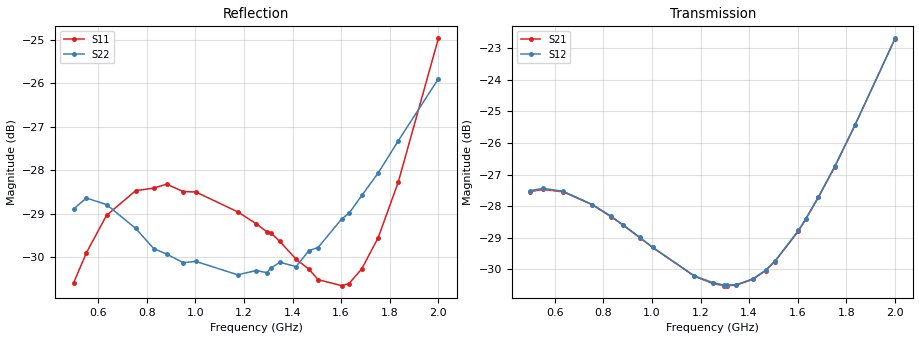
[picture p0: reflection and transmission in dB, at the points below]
!Agilent Technologies,E8363B,SG43030131,A.07.50.48
!Agilent E8363B: A.07.50.48
!Date: Wednesday, October 22, 2025 01:53:43
!Correction: S11(Full 2 Port(1,2))
!S21(Full 2 Port(1,2))
!S12(Full 2 Port(1,2))
!S22(Full 2 Port(1,2))
!S2P File: Measurements: S11, S21, S12, S22:
# Hz S  dB  R 50
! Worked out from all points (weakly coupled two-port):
!   201 points, 500 MHz to 2 GHz, reference 50 ohm
!   highest |S21| = -22.70 dB at 2 GHz (marker M1); lowest = -30.5 dB at 1.31 GHz (marker M2)
!   lowest |S11| = -30.7 dB at 1.603 GHz (marker M3), VSWR 1.06, Z = 48.7 - j2.58 ohm
!   |S11| at or under -10 dB: start of sweep to end of sweep
!   |S22| runs from -30.4 to -25.9 dB; largest |S21 - S12| = 0.00028
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5e8  -30.59 104.6  -27.54 -40.4  -27.51 -40.4  -28.89 161.1
5.525e8  -29.90 91.8  -27.47 -51.4  -27.44 -51.6  -28.64 151.0
6.35e8  -29.04 72.2  -27.55 -67.7  -27.53 -67.8  -28.79 135.5
7.55e8  -28.47 48.9  -27.96 -88.9  -27.95 -88.9  -29.34 113.8
8.3e8  -28.41 35.5  -28.33 -100.7  -28.31 -100.8  -29.81 100.6
8.825e8  -28.32 27.0  -28.61 -108.4  -28.60 -108.5  -29.93 90.8
9.5e8  -28.49 15.7  -29.00 -117.6  -28.99 -117.6  -30.13 79.1
1.0025e9  -28.50 7.2  -29.31 -124.0  -29.30 -124.1  -30.10 70.8
1.175e9  -28.96 -21.1  -30.22 -141.3  -30.21 -141.4  -30.41 45.1
1.25e9  -29.23 -33.4  -30.45 -147.0  -30.42 -147.1  -30.31 34.5
1.295e9  -29.42 -42.0  -30.52 -149.9  -30.50 -150.1  -30.36 27.4
1.31e9  -29.44 -44.9  -30.52 -150.8  -30.50 -150.9  -30.26 25.1
1.3475e9  -29.64 -51.6  -30.50 -153.0  -30.49 -153.2  -30.12 20.3
1.415e9  -30.05 -66.6  -30.32 -156.7  -30.30 -156.8  -30.22 9.7
1.4675e9  -30.28 -78.4  -30.04 -159.5  -30.03 -159.5  -29.85 1.5
1.505e9  -30.52 -88.1  -29.76 -161.5  -29.75 -161.5  -29.78 -3.8
1.6025e9  -30.66 -115.6  -28.79 -167.5  -28.77 -167.6  -29.12 -19.3
1.6325e9  -30.61 -125.3  -28.42 -169.7  -28.40 -169.8  -28.99 -23.9
1.685e9  -30.27 -142.1  -27.72 -173.9  -27.70 -174.0  -28.58 -32.9
1.7525e9  -29.55 -164.2  -26.75 179.9  -26.73 179.8  -28.06 -43.9
1.835e9  -28.27 169.5  -25.44 171.0  -25.43 171.0  -27.32 -57.7
2e9  -24.96 122.0  -22.70 149.1  -22.69 149.1  -25.89 -88.3
